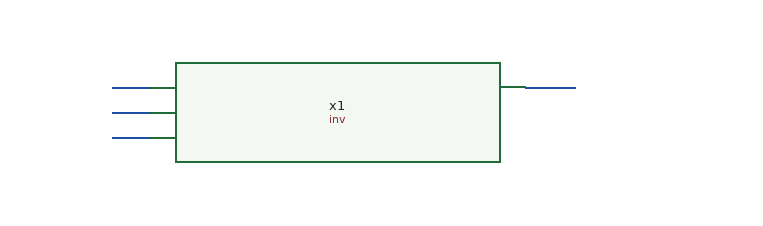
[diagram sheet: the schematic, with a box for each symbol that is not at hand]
v {xschem version=3.4.5 file_version=1.2
}
G {}
K {}
V {}
S {}
E {}
N -170 -20 -140 -20 {
lab=#net1}
N -170 0 -140 0 {
lab=#net2}
N -170 20 -140 20 {
lab=#net3}
N 160 -20 200 -20 {
lab=#net4}
C {inv.sym} 10 0 0 0 {name=x1}
C {devices/noconn.sym} -170 -20 0 0 {name=l1}
C {devices/noconn.sym} -170 0 0 0 {name=l2}
C {devices/noconn.sym} -170 20 0 0 {name=l3}
C {devices/noconn.sym} 200 -20 0 1 {name=l4}
